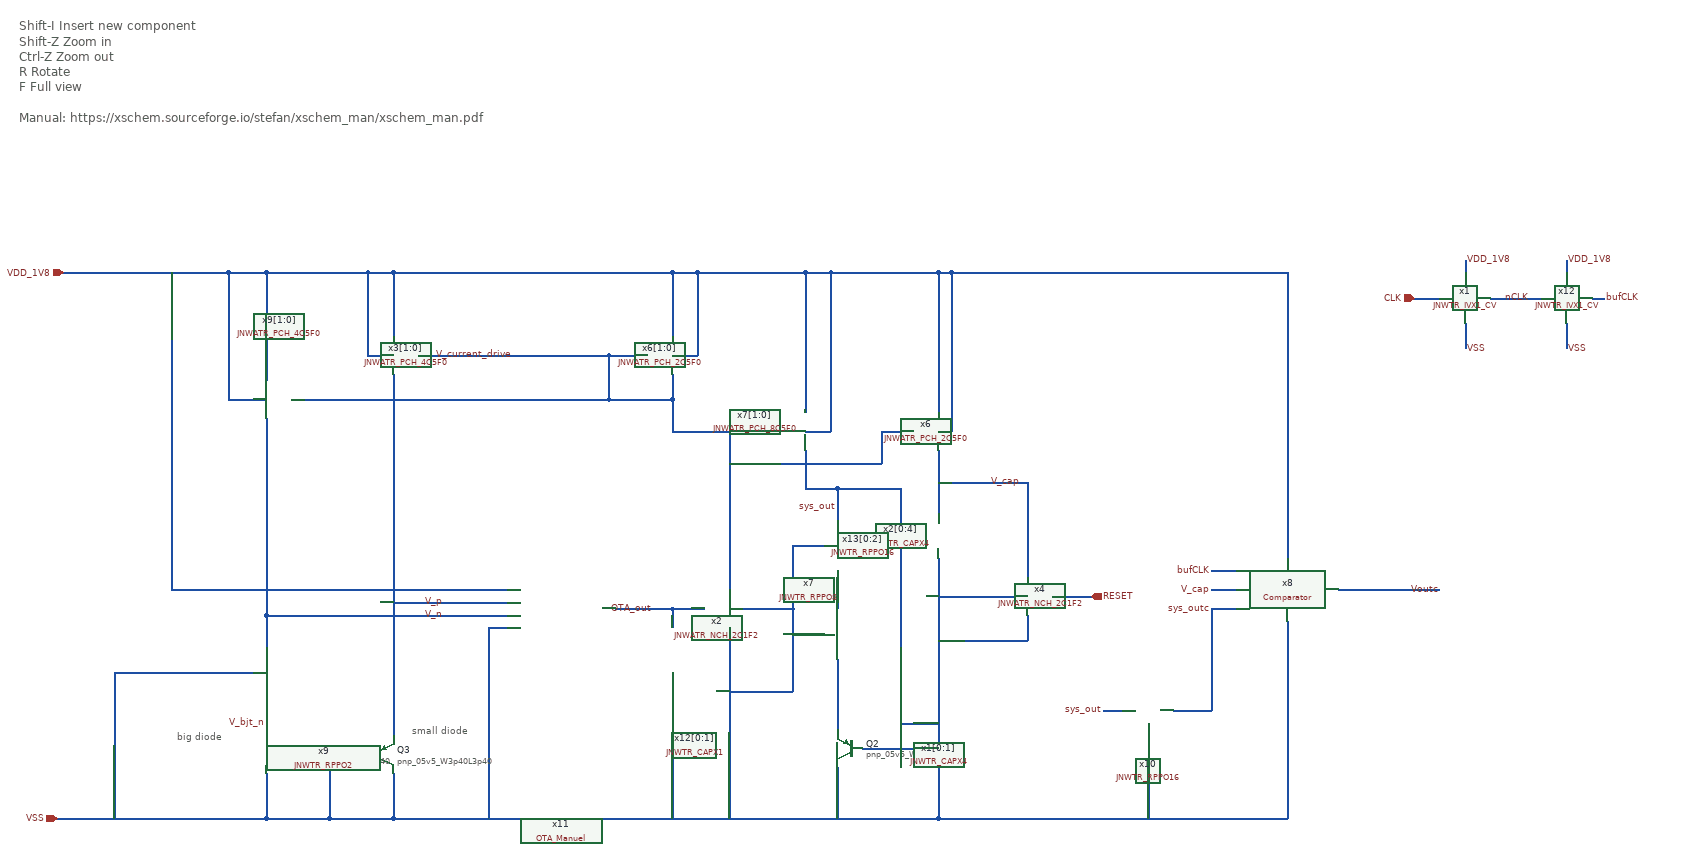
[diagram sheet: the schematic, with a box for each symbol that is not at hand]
v {xschem version=3.4.6 file_version=1.2}
G {}
K {}
V {}
S {}
E {}
T {Shift-I          Insert new component
Shift-Z         Zoom in
Ctrl-Z           Zoom out
R                 Rotate
F                 Full view

Manual: https://xschem.sourceforge.io/stefan/xschem_man/xschem_man.pdf
} -1500 -1380 0 0 0.6 0.6 {}
T {big diode
} -1250 -260 0 0 0.4 0.4 {}
T {small diode
} -880 -270 0 0 0.4 0.4 {}
N -1110 -310 -1110 -250 {
lab=V_bjt_n}
N -1010 -220 -950 -220 {
lab=VSS}
N -1110 -190 -1110 -120 {
lab=VSS}
N -910 -190 -910 -120 {
lab=VSS}
N -1010 -220 -1010 -120 {
lab=VSS}
N -1010 -120 -910 -120 {
lab=VSS}
N -1230 -120 -1110 -120 {
lab=VSS}
N -1110 -440 -1110 -390 {
lab=V_n}
N -910 -120 -830 -120 {
lab=VSS}
N -1110 -980 -950 -980 {
lab=VDD_1V8}
N -470 -450 -420 -450 {
lab=OTA_out}
N -380 -450 -340 -450 {
lab=VSS}
N -910 -980 -470 -980 {
lab=VDD_1V8}
N -470 -980 -430 -980 {
lab=VDD_1V8}
N -380 -730 -380 -480 {
lab=V_current_drive}
N -470 -980 -470 -880 {
lab=VDD_1V8}
N -470 -850 -430 -850 {
lab=VDD_1V8}
N -430 -980 -430 -850 {
lab=VDD_1V8}
N -570 -850 -570 -780 {
lab=V_current_drive}
N -1260 -980 -1260 -480 {
lab=VDD_1V8}
N -1430 -980 -1170 -980 {
lab=VDD_1V8}
N -910 -980 -910 -880 {
lab=VDD_1V8}
N -950 -980 -950 -850 {
lab=VDD_1V8}
N -570 -850 -510 -850 {
lab=V_current_drive}
N -950 -850 -910 -850 {
lab=VDD_1V8}
N -260 -700 -260 -640 {
lab=sys_out}
N -430 -980 -260 -980 {
lab=VDD_1V8}
N -260 -730 -220 -730 {
lab=VDD_1V8}
N -260 -980 -220 -980 {
lab=VDD_1V8}
N -470 -730 -300 -730 {
lab=V_current_drive}
N -570 -780 -470 -780 {
lab=V_current_drive}
N -1170 -780 -1110 -780 {
lab=VDD_1V8}
N -1170 -980 -1170 -780 {
lab=VDD_1V8}
N -1110 -980 -1110 -810 {
lab=VDD_1V8}
N -260 -980 -260 -760 {
lab=VDD_1V8}
N -220 -980 -220 -730 {
lab=VDD_1V8}
N -1230 -350 -1130 -350 {
lab=VSS}
N -1350 -350 -1350 -120 {
lab=VSS}
N -470 -350 -470 -300 {
lab=VSS}
N -470 -450 -470 -420 {
lab=OTA_out}
N -1070 -220 -1010 -220 {
lab=VSS}
N -1110 -120 -1010 -120 {
lab=VSS}
N -380 -420 -380 -340 {
lab=VSS}
N -870 -850 -570 -850 {
lab=V_current_drive}
N -1070 -780 -570 -780 {
lab=V_current_drive}
N -470 -820 -470 -780 {
lab=V_current_drive}
N -950 -980 -910 -980 {
lab=VDD_1V8}
N -470 -780 -470 -730 {
lab=V_current_drive}
N -1170 -980 -1110 -980 {
lab=VDD_1V8}
N -1260 -120 -1230 -120 {
lab=VSS}
N -830 -460 -800 -460 {
lab=V_p}
N -910 -820 -910 -250 {
lab=V_p}
N -830 -440 -800 -440 {
lab=V_n}
N -1110 -440 -830 -440 {
lab=V_n}
N -910 -460 -830 -460 {
lab=V_p}
N -210 -370 -210 -320 {
lab=#net1}
N -830 -120 -340 -120 {
lab=VSS}
N -470 -300 -470 -120 {
lab=VSS}
N -1440 -120 -1260 -120 {lab=VSS}
N -1350 -350 -1230 -350 {lab=VSS}
N -1260 -480 -800 -480 {lab=VDD_1V8}
N -560 -450 -470 -450 {lab=OTA_out}
N -800 -480 -730 -480 {lab=VDD_1V8}
N -800 -460 -730 -460 {lab=V_p}
N -800 -440 -730 -440 {lab=V_n}
N -760 -420 -740 -420 {lab=VSS}
N -760 -420 -760 -120 {lab=VSS}
N -740 -420 -730 -420 {lab=VSS}
N -260 -640 -210 -640 {lab=sys_out}
N -210 -320 -210 -300 {lab=#net1}
N -50 -530 -50 -120 {lab=VSS}
N -340 -120 -50 -120 {lab=VSS}
N -50 -700 -50 -600 {lab=V_cap}
N -380 -680 -140 -680 {lab=V_current_drive}
N -140 -730 -140 -680 {lab=V_current_drive}
N -140 -730 -90 -730 {lab=V_current_drive}
N -220 -980 -50 -980 {lab=VDD_1V8}
N -50 -980 -50 -760 {lab=VDD_1V8}
N -50 -730 -30 -730 {lab=VDD_1V8}
N -30 -980 -30 -730 {lab=VDD_1V8}
N -50 -980 -30 -980 {lab=VDD_1V8}
N -50 -650 90 -650 {lab=V_cap}
N 90 -650 90 -500 {lab=V_cap}
N -50 -470 90 -470 {lab=VSS}
N 90 -440 90 -400 {lab=VSS}
N -50 -400 90 -400 {lab=VSS}
N 130 -470 190 -470 {lab=RESET}
N -1110 -540 -1110 -440 {lab=V_n}
N 500 -980 500 -570 {lab=VDD_1V8}
N -30 -980 500 -980 {lab=VDD_1V8}
N -50 -120 500 -120 {lab=VSS}
N 500 -390 500 -120 {lab=VSS}
N -210 -300 -210 -260 {lab=#net1}
N -170 -230 -60 -230 {lab=VSS}
N -60 -230 -50 -230 {lab=VSS}
N -210 -200 -210 -120 {lab=VSS}
N -1110 -750 -1110 -540 {lab=V_n}
N -110 -470 -110 -390 {lab=sys_out}
N -110 -320 -110 -270 {lab=VSS}
N -110 -270 -50 -270 {lab=VSS}
N -210 -640 -210 -590 {lab=sys_out}
N -110 -640 -110 -470 {lab=sys_out}
N -210 -640 -110 -640 {lab=sys_out}
N -380 -340 -380 -120 {lab=VSS}
N -280 -360 -280 -320 {lab=VSS}
N -380 -320 -280 -320 {lab=VSS}
N -280 -410 -230 -410 {lab=VSS}
N -210 -510 -210 -450 {lab=#net2}
N -340 -450 -280 -450 {lab=VSS}
N -280 -450 -280 -360 {lab=VSS}
N 210 -290 240 -290 {lab=sys_out}
N 700 -940 740 -940 {lab=CLK}
N 820 -940 840 -940 {lab=nCLK}
N 780 -1000 780 -980 {lab=VDD_1V8}
N 780 -900 780 -860 {lab=VSS}
N 380 -400 380 -290 {lab=#net3}
N 980 -940 1000 -940 {lab=bufCLK}
N 840 -940 900 -940 {lab=nCLK}
N 320 -290 380 -290 {lab=#net3}
N 280 -270 280 -120 {lab=VSS}
N 940 -1000 940 -980 {lab=VDD_1V8}
N 940 -900 940 -860 {lab=VSS}
N -280 -550 -230 -550 {lab=VSS}
N -280 -550 -280 -450 {lab=VSS}
N 500 -570 500 -530 {lab=VDD_1V8}
N 500 -430 500 -390 {lab=VSS}
N 580 -480 740 -480 {lab=Voutc}
N 380 -510 420 -510 {lab=bufCLK}
N 380 -450 420 -450 {lab=#net3}
N 380 -480 420 -480 {lab=V_cap}
N 380 -450 380 -400 {lab=#net3}
C {devices/ipin.sym} -1430 -980 0 0 {name=p1 lab=VDD_1V8}
C {devices/ipin.sym} -1440 -120 0 0 {name=p8 lab=VSS}
C {JNW_ATR_SKY130A/JNWATR_PCH_4C5F0.sym} -1070 -780 0 1 {name=x9[1:0]}
C {JNW_ATR_SKY130A/JNWATR_PCH_2C5F0.sym} -510 -850 0 0 {name=x6[1:0]}
C {JNW_ATR_SKY130A/JNWATR_PCH_8C5F0.sym} -300 -730 0 0 {name=x7[1:0]}
C {sky130_fd_pr/pnp_05v5.sym} -930 -220 0 0 {name=Q3
model=pnp_05v5_W3p40L3p40
m=1
spiceprefix=X
}
C {sky130_fd_pr/pnp_05v5.sym} -1090 -220 0 1 {name=Q1
model=pnp_05v5_W3p40L3p40
m=5
spiceprefix=X
}
C {devices/lab_wire.sym} -500 -450 0 0 {name=p10 sig_type=std_logic lab=OTA_out}
C {devices/lab_wire.sym} -720 -850 0 0 {name=p11 sig_type=std_logic lab=V_current_drive}
C {devices/lab_wire.sym} -830 -460 0 0 {name=p12 sig_type=std_logic lab=V_p}
C {devices/lab_wire.sym} -830 -440 0 0 {name=p13 sig_type=std_logic lab=V_n}
C {JNW_GR05_SKY130A/OTA_Manuel.sym} -580 -450 0 0 {name=x11}
C {devices/lab_wire.sym} -1110 -270 0 0 {name=p15 sig_type=std_logic lab=V_bjt_n}
C {JNW_ATR_SKY130A/JNWATR_NCH_2C1F2.sym} -420 -450 0 0 {name=x2 }
C {JNW_TR_SKY130A/JNWTR_RPPO2.sym} -1110 -390 1 0 {name=x9}
C {JNW_ATR_SKY130A/JNWATR_PCH_2C5F0.sym} -90 -730 0 0 {name=x6}
C {JNW_ATR_SKY130A/JNWATR_NCH_2C1F2.sym} 130 -470 0 1 {name=x4 }
C {devices/ipin.sym} 190 -470 0 1 {name=p5 lab=RESET
}
C {JNW_TR_SKY130A/JNWTR_CAPX4.sym} -50 -540 0 0 {name=x2[0:4]}
C {devices/lab_wire.sym} -210 -610 0 0 {name=p7 sig_type=std_logic lab=sys_out}
C {JNW_GR05_SKY130A/Comparator.sym} 500 -480 0 0 {name=x8}
C {devices/lab_wire.sym} 80 -650 0 0 {name=p17 sig_type=std_logic lab=V_cap}
C {devices/lab_wire.sym} 380 -480 0 0 {name=p18 sig_type=std_logic lab=V_cap}
C {devices/lab_wire.sym} 210 -290 0 0 {name=p19 sig_type=std_logic lab=sys_out}
C {JNW_TR_SKY130A/JNWTR_CAPX1.sym} -470 -360 0 0 {name=x12[0:1]}
C {sky130_fd_pr/pnp_05v5.sym} -190 -230 0 1 {name=Q2
model=pnp_05v5_W3p40L3p40
m=1
spiceprefix=X
}
C {JNW_ATR_SKY130A/JNWATR_PCH_4C5F0.sym} -870 -850 0 1 {name=x3[1:0]}
C {JNW_TR_SKY130A/JNWTR_CAPX4.sym} -110 -330 0 0 {name=x1[0:1]}
C {JNW_TR_SKY130A/JNWTR_IVX1_CV.sym} 740 -940 0 0 {name=x1 }
C {devices/lab_wire.sym} 840 -940 0 1 {name=p6 sig_type=std_logic lab=nCLK}
C {devices/lab_wire.sym} 780 -1000 0 1 {name=p21 sig_type=std_logic lab=VDD_1V8
}
C {devices/lab_wire.sym} 780 -860 0 1 {name=p22 sig_type=std_logic lab=VSS
}
C {devices/lab_wire.sym} 1000 -940 0 1 {name=p27 sig_type=std_logic lab=bufCLK}
C {devices/lab_wire.sym} 380 -510 0 0 {name=p9 sig_type=std_logic lab=bufCLK}
C {JNW_TR_SKY130A/JNWTR_RPPO16.sym} 240 -290 0 0 {name=x10}
C {JNW_TR_SKY130A/JNWTR_IVX1_CV.sym} 900 -940 0 0 {name=x12 }
C {devices/lab_wire.sym} 940 -1000 0 1 {name=p26 sig_type=std_logic lab=VDD_1V8
}
C {devices/lab_wire.sym} 940 -860 0 1 {name=p28 sig_type=std_logic lab=VSS
}
C {JNW_TR_SKY130A/JNWTR_RPPO8.sym} -210 -450 1 0 {name=x7}
C {JNW_TR_SKY130A/JNWTR_RPPO16.sym} -210 -590 1 0 {name=x13[0:2]}
C {devices/lab_wire.sym} 740 -480 0 0 {name=p2 sig_type=std_logic lab=Voutc}
C {devices/ipin.sym} 700 -940 0 0 {name=p14 lab=CLK
}
C {devices/lab_wire.sym} 380 -450 0 0 {name=p3 sig_type=std_logic lab=sys_outc}
